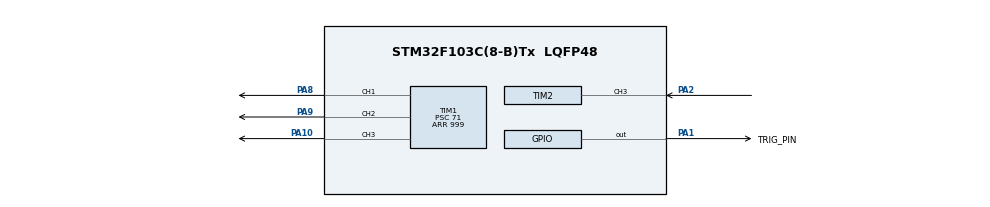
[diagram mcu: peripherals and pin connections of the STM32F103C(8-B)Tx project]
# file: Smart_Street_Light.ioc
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Mcu.Family=STM32F1
Mcu.Name=STM32F103C(8-B)Tx
Mcu.Package=LQFP48
NVIC.PriorityGroup=NVIC_PRIORITYGROUP_4
NVIC.TIM2_IRQn=true\:0\:0\:false\:false\:true\:true\:true\:true
PA1.GPIO_Label=TRIG_PIN
PA1.Signal=GPIO_Output
PA10.Signal=S_TIM1_CH3
PA13.Mode=Serial_Wire
PA13.Signal=SYS_JTMS-SWDIO
PA14.Mode=Serial_Wire
PA14.Signal=SYS_JTCK-SWCLK
PA2.Signal=S_TIM2_CH3
PA8.Signal=S_TIM1_CH1
PA9.Signal=S_TIM1_CH2
PD0-OSC_IN.Signal=RCC_OSC_IN
PD1-OSC_OUT.Signal=RCC_OSC_OUT
ProjectManager.HeapSize=0x200
ProjectManager.StackSize=0x400
ProjectManager.TargetToolchain=STM32CubeIDE
RCC.AHBFreq_Value=64000000
RCC.APB1CLKDivider=RCC_HCLK_DIV2
RCC.APB1Freq_Value=32000000
RCC.APB1TimFreq_Value=64000000
RCC.APB2Freq_Value=64000000
RCC.APB2TimFreq_Value=64000000
RCC.HCLKFreq_Value=64000000
RCC.PLLMUL=RCC_PLL_MUL16
RCC.SYSCLKFreq_VALUE=64000000
RCC.SYSCLKSource=RCC_SYSCLKSOURCE_PLLCLK
RCC.USBFreq_Value=64000000
SH.S_TIM1_CH1.0=TIM1_CH1,PWM Generation1 CH1
SH.S_TIM1_CH2.0=TIM1_CH2,PWM Generation2 CH2
SH.S_TIM1_CH3.0=TIM1_CH3,PWM Generation3 CH3
SH.S_TIM2_CH3.0=TIM2_CH3,Input_Capture3_from_TI3
TIM1.Channel-PWM\ Generation1\ CH1=TIM_CHANNEL_1
TIM1.Channel-PWM\ Generation2\ CH2=TIM_CHANNEL_2
TIM1.Channel-PWM\ Generation3\ CH3=TIM_CHANNEL_3
TIM1.Period=999
TIM1.Prescaler=71
TIM2.Channel-Input_Capture3_from_TI3=TIM_CHANNEL_3
TIM2.Prescaler=35
board=custom

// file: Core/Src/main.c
/* USER CODE BEGIN Header */
/**
  ******************************************************************************
  * @file           : main.c
  * @brief          : Main program body for Smart Street Light
  ******************************************************************************
  */
/* USER CODE END Header */
#include "main.h"

/* USER CODE BEGIN PD */
#define TRIG_PIN GPIO_PIN_1
#define TRIG_PORT GPIOA
// ECHO is on PA2, which is TIM2 Channel 3

#define RGB_RED_PIN GPIO_PIN_8
#define RGB_RED_PORT GPIOA
#define RGB_GREEN_PIN GPIO_PIN_9
#define RGB_GREEN_PORT GPIOA
#define RGB_BLUE_PIN GPIO_PIN_10
#define RGB_BLUE_PORT GPIOA

#define PWM_MAX_DUTY_CYCLE 999

#define MIN_DIST_CM 5
#define MAX_DIST_CM 50
#define MIN_BRIGHTNESS_PWM (PWM_MAX_DUTY_CYCLE / 10)
#define MAX_BRIGHTNESS_PWM (PWM_MAX_DUTY_CYCLE * 9 / 10)
/* USER CODE END PD */

TIM_HandleTypeDef htim1;
TIM_HandleTypeDef htim2;

/* USER CODE BEGIN PV */
volatile uint32_t IC_Val1 = 0;
volatile uint32_t IC_Val2 = 0;
volatile uint32_t Difference = 0;
volatile uint8_t Is_First_Captured = 0;
volatile float Distance = 0;
/* USER CODE END PV */

void SystemClock_Config(void);
static void MX_GPIO_Init(void);
static void MX_TIM1_Init(void);
static void MX_TIM2_Init(void);
/* USER CODE BEGIN PFP */
void HCSR04_ReadDistance(void);
void SetRGBBrightness(uint32_t brightness_pwm);
uint32_t Map(uint32_t x, uint32_t in_min, uint32_t in_max, uint32_t out_min, uint32_t out_max);
void HAL_Delay_microseconds(uint32_t us);
/* USER CODE END PFP */

int main(void)
{

  /* MCU Configuration--------------------------------------------------------*/
  HAL_Init();

  /* Configure the system clock */
  SystemClock_Config();

  /* Initialize all configured peripherals */
  MX_GPIO_Init();
  MX_TIM1_Init();
  MX_TIM2_Init();

  /* USER CODE BEGIN 2 */
  // Start PWM for LEDs
  HAL_TIM_PWM_Start(&htim1, TIM_CHANNEL_1);
  HAL_TIM_PWM_Start(&htim1, TIM_CHANNEL_2);
  HAL_TIM_PWM_Start(&htim1, TIM_CHANNEL_3);

  // Start Input Capture on TIM2 Channel 3 (PA2)
  HAL_TIM_IC_Start_IT(&htim2, TIM_CHANNEL_3);
  /* USER CODE END 2 */

  /* Infinite loop */
  /* USER CODE BEGIN WHILE */
  while (1)
  {
    HCSR04_ReadDistance();

    uint32_t brightness_pwm_value;

    // LOGIC: Map Distance to Brightness
    if (Distance <= 0.1) {
        // Sensor Error or Timeout -> Full Brightness for safety
        brightness_pwm_value = MAX_BRIGHTNESS_PWM;
    }
    else if (Distance <= MIN_DIST_CM) {
        brightness_pwm_value = MAX_BRIGHTNESS_PWM;
    }
    else if (Distance >= MAX_DIST_CM) {
        brightness_pwm_value = MIN_BRIGHTNESS_PWM;
    }
    else {
        // Inverse: Closer = Brighter
        brightness_pwm_value = Map((uint32_t)Distance, MIN_DIST_CM, MAX_DIST_CM, MAX_BRIGHTNESS_PWM, MIN_BRIGHTNESS_PWM);
    }

    SetRGBBrightness(brightness_pwm_value);

    // Heartbeat: Blink Blue LED slightly to show code is running
    // If the LEDs are flickering, it means the loop is working.
    // HAL_GPIO_TogglePin(GPIOC, GPIO_PIN_13); // Onboard LED if you have one

    HAL_Delay(100);

    /* USER CODE END WHILE */

  }
}

void SystemClock_Config(void)
{
  RCC_OscInitTypeDef RCC_OscInitStruct = {0};
  RCC_ClkInitTypeDef RCC_ClkInitStruct = {0};

  RCC_OscInitStruct.OscillatorType = RCC_OSCILLATORTYPE_HSE;
  RCC_OscInitStruct.HSEState = RCC_HSE_ON;
  RCC_OscInitStruct.HSEPredivValue = RCC_HSE_PREDIV_DIV1;
  RCC_OscInitStruct.HSIState = RCC_HSI_ON;
  RCC_OscInitStruct.PLL.PLLState = RCC_PLL_ON;
  RCC_OscInitStruct.PLL.PLLSource = RCC_PLLSOURCE_HSE;
  RCC_OscInitStruct.PLL.PLLMUL = RCC_PLL_MUL9;
  if (HAL_RCC_OscConfig(&RCC_OscInitStruct) != HAL_OK)
  {
    Error_Handler();
  }

  RCC_ClkInitStruct.ClockType = RCC_CLOCKTYPE_HCLK|RCC_CLOCKTYPE_SYSCLK
                              |RCC_CLOCKTYPE_PCLK1|RCC_CLOCKTYPE_PCLK2;
  RCC_ClkInitStruct.SYSCLKSource = RCC_SYSCLKSOURCE_PLLCLK;
  RCC_ClkInitStruct.AHBCLKDivider = RCC_SYSCLK_DIV1;
  RCC_ClkInitStruct.APB1CLKDivider = RCC_HCLK_DIV2;
  RCC_ClkInitStruct.APB2CLKDivider = RCC_HCLK_DIV1;

  if (HAL_RCC_ClockConfig(&RCC_ClkInitStruct, FLASH_LATENCY_2) != HAL_OK)
  {
    Error_Handler();
  }
}

static void MX_TIM1_Init(void)
{
  TIM_MasterConfigTypeDef sMasterConfig = {0};
  TIM_OC_InitTypeDef sConfigOC = {0};
  TIM_BreakDeadTimeConfigTypeDef sBreakDeadTimeConfig = {0};

  htim1.Instance = TIM1;
  htim1.Init.Prescaler = 71;
  htim1.Init.CounterMode = TIM_COUNTERMODE_UP;
  htim1.Init.Period = 999;
  htim1.Init.ClockDivision = TIM_CLOCKDIVISION_DIV1;
  htim1.Init.RepetitionCounter = 0;
  htim1.Init.AutoReloadPreload = TIM_AUTORELOAD_PRELOAD_DISABLE;
  if (HAL_TIM_Base_Init(&htim1) != HAL_OK)
  {
    Error_Handler();
  }
  if (HAL_TIM_PWM_Init(&htim1) != HAL_OK)
  {
    Error_Handler();
  }
  sMasterConfig.MasterOutputTrigger = TIM_TRGO_RESET;
  sMasterConfig.MasterSlaveMode = TIM_MASTERSLAVEMODE_DISABLE;
  if (HAL_TIMEx_MasterConfigSynchronization(&htim1, &sMasterConfig) != HAL_OK)
  {
    Error_Handler();
  }
  sConfigOC.OCMode = TIM_OCMODE_PWM1;
  sConfigOC.Pulse = 0;
  sConfigOC.OCPolarity = TIM_OCPOLARITY_HIGH;
  sConfigOC.OCNPolarity = TIM_OCNPOLARITY_HIGH;
  sConfigOC.OCFastMode = TIM_OCFAST_DISABLE;
  sConfigOC.OCIdleState = TIM_OCIDLESTATE_RESET;
  sConfigOC.OCNIdleState = TIM_OCNIDLESTATE_RESET;
  if (HAL_TIM_PWM_ConfigChannel(&htim1, &sConfigOC, TIM_CHANNEL_1) != HAL_OK)
  {
    Error_Handler();
  }
  if (HAL_TIM_PWM_ConfigChannel(&htim1, &sConfigOC, TIM_CHANNEL_2) != HAL_OK)
  {
    Error_Handler();
  }
  if (HAL_TIM_PWM_ConfigChannel(&htim1, &sConfigOC, TIM_CHANNEL_3) != HAL_OK)
  {
    Error_Handler();
  }
  sBreakDeadTimeConfig.OffStateRunMode = TIM_OSSR_DISABLE;
  sBreakDeadTimeConfig.OffStateIDLEMode = TIM_OSSI_DISABLE;
  sBreakDeadTimeConfig.LockLevel = TIM_LOCKLEVEL_OFF;
  sBreakDeadTimeConfig.DeadTime = 0;
  sBreakDeadTimeConfig.BreakState = TIM_BREAK_DISABLE;
  sBreakDeadTimeConfig.BreakPolarity = TIM_BREAKPOLARITY_HIGH;
  sBreakDeadTimeConfig.AutomaticOutput = TIM_AUTOMATICOUTPUT_DISABLE;
  if (HAL_TIMEx_ConfigBreakDeadTime(&htim1, &sBreakDeadTimeConfig) != HAL_OK)
  {
    Error_Handler();
  }
  HAL_TIM_MspPostInit(&htim1);
}

static void MX_TIM2_Init(void)
{
  TIM_MasterConfigTypeDef sMasterConfig = {0};
  TIM_IC_InitTypeDef sConfigIC = {0};

  htim2.Instance = TIM2;
  htim2.Init.Prescaler = 35;
  htim2.Init.CounterMode = TIM_COUNTERMODE_UP;
  htim2.Init.Period = 65535;
  htim2.Init.ClockDivision = TIM_CLOCKDIVISION_DIV1;
  htim2.Init.AutoReloadPreload = TIM_AUTORELOAD_PRELOAD_DISABLE;
  if (HAL_TIM_Base_Init(&htim2) != HAL_OK)
  {
    Error_Handler();
  }
  if (HAL_TIM_IC_Init(&htim2) != HAL_OK)
  {
    Error_Handler();
  }
  sMasterConfig.MasterOutputTrigger = TIM_TRGO_RESET;
  sMasterConfig.MasterSlaveMode = TIM_MASTERSLAVEMODE_DISABLE;
  if (HAL_TIMEx_MasterConfigSynchronization(&htim2, &sMasterConfig) != HAL_OK)
  {
    Error_Handler();
  }
  // CONFIGURING CHANNEL 3 HERE
  sConfigIC.ICPolarity = TIM_INPUTCHANNELPOLARITY_RISING;
  sConfigIC.ICSelection = TIM_ICSELECTION_DIRECTTI;
  sConfigIC.ICPrescaler = TIM_ICPSC_DIV1;
  sConfigIC.ICFilter = 0;
  if (HAL_TIM_IC_ConfigChannel(&htim2, &sConfigIC, TIM_CHANNEL_3) != HAL_OK)
  {
    Error_Handler();
  }
}

static void MX_GPIO_Init(void)
{
  GPIO_InitTypeDef GPIO_InitStruct = {0};

  /* GPIO Ports Clock Enable */
  __HAL_RCC_GPIOD_CLK_ENABLE();
  __HAL_RCC_GPIOA_CLK_ENABLE();
  __HAL_RCC_GPIOB_CLK_ENABLE();

  /*Configure GPIO pin Output Level */
  HAL_GPIO_WritePin(TRIG_PORT, TRIG_PIN, GPIO_PIN_RESET);

  /*Configure GPIO pin : TRIG_PIN */
  GPIO_InitStruct.Pin = TRIG_PIN;
  GPIO_InitStruct.Mode = GPIO_MODE_OUTPUT_PP;
  GPIO_InitStruct.Pull = GPIO_NOPULL;
  GPIO_InitStruct.Speed = GPIO_SPEED_FREQ_LOW;
  HAL_GPIO_Init(TRIG_PORT, &GPIO_InitStruct);
}

/* USER CODE BEGIN 4 */

// Callback modified for CHANNEL 3
void HAL_TIM_IC_CaptureCallback(TIM_HandleTypeDef *htim)
{
  if (htim->Instance == TIM2)
  {
      // Removed specific channel check to be permissive
      if (Is_First_Captured == 0)
      {
        IC_Val1 = HAL_TIM_ReadCapturedValue(htim, TIM_CHANNEL_3);
        Is_First_Captured = 1;
        __HAL_TIM_SET_CAPTUREPOLARITY(htim, TIM_CHANNEL_3, TIM_INPUTCHANNELPOLARITY_FALLING);
      }
      else if (Is_First_Captured == 1)
      {
        IC_Val2 = HAL_TIM_ReadCapturedValue(htim, TIM_CHANNEL_3);

        if (IC_Val2 > IC_Val1)
        {
          Difference = IC_Val2 - IC_Val1;
        }
        else
        {
          Difference = (0xFFFFFFFF - IC_Val1) + IC_Val2;
        }

        Distance = (float)Difference * 0.0343 / 2;
        Is_First_Captured = 0;

        __HAL_TIM_SET_COUNTER(htim, 0);
        __HAL_TIM_SET_CAPTUREPOLARITY(htim, TIM_CHANNEL_3, TIM_INPUTCHANNELPOLARITY_RISING);
      }
  }
}

void HCSR04_ReadDistance(void)
{
  HAL_GPIO_WritePin(TRIG_PORT, TRIG_PIN, GPIO_PIN_SET);
  HAL_Delay_microseconds(10);
  HAL_GPIO_WritePin(TRIG_PORT, TRIG_PIN, GPIO_PIN_RESET);
}

void SetRGBBrightness(uint32_t brightness_pwm)
{
  __HAL_TIM_SET_COMPARE(&htim1, TIM_CHANNEL_1, brightness_pwm); // Red
  __HAL_TIM_SET_COMPARE(&htim1, TIM_CHANNEL_2, brightness_pwm); // Green
  __HAL_TIM_SET_COMPARE(&htim1, TIM_CHANNEL_3, brightness_pwm); // Blue
}

uint32_t Map(uint32_t x, uint32_t in_min, uint32_t in_max, uint32_t out_min, uint32_t out_max) {
    if (x < in_min) return out_min;
    if (x > in_max) return out_max;
    return (x - in_min) * (out_max - out_min) / (in_max - in_min) + out_min;
}

void HAL_Delay_microseconds(uint32_t us)
{
    // Approx delay for 72MHz
    for(uint32_t i=0; i < us * 12; i++) {
        __NOP();
    }
}
/* USER CODE END 4 */

void Error_Handler(void)
{
  __disable_irq();
  while (1)
  {
  }
}
